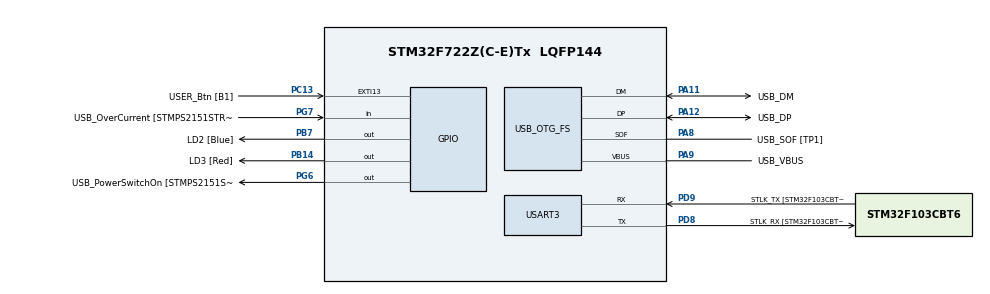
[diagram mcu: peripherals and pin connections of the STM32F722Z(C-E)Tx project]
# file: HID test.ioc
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Mcu.Family=STM32F7
Mcu.Name=STM32F722Z(C-E)Tx
Mcu.Package=LQFP144
NVIC.OTG_FS_IRQn=true\:0\:0\:false\:false\:true\:false
NVIC.PriorityGroup=NVIC_PRIORITYGROUP_4
PA10.GPIO_Label=USB_ID
PA10.Signal=USB_OTG_FS_ID
PA11.GPIO_Label=USB_DM
PA11.Mode=Device_Only
PA11.Signal=USB_OTG_FS_DM
PA12.GPIO_Label=USB_DP
PA12.Mode=Device_Only
PA12.Signal=USB_OTG_FS_DP
PA13.GPIO_Label=TMS
PA13.Mode=Serial_Wire
PA13.Signal=SYS_JTMS-SWDIO
PA14.GPIO_Label=TCK
PA14.Mode=Serial_Wire
PA14.Signal=SYS_JTCK-SWCLK
PA8.GPIO_Label=USB_SOF [TP1]
PA8.Mode=Activate_SOF_FS
PA8.Signal=USB_OTG_FS_SOF
PA9.GPIO_Label=USB_VBUS
PA9.Mode=Activate_VBUS
PA9.Signal=USB_OTG_FS_VBUS
PB14.GPIO_Label=LD3 [Red]
PB14.Signal=GPIO_Output
PB3.GPIO_Label=SWO
PB3.Signal=SYS_JTDO-SWO
PB7.GPIO_Label=LD2 [Blue]
PB7.Signal=GPIO_Output
PC13.GPIO_Label=USER_Btn [B1]
PC13.Signal=GPXTI13
PC14-OSC32_IN.Mode=LSE-External-Oscillator
PC14-OSC32_IN.Signal=RCC_OSC32_IN
PC15-OSC32_OUT.Mode=LSE-External-Oscillator
PC15-OSC32_OUT.Signal=RCC_OSC32_OUT
PD8.GPIO_Label=STLK_RX [STM32F103CBT6_PA3]
PD8.Mode=Asynchronous
PD8.Signal=USART3_TX
PD9.GPIO_Label=STLK_TX [STM32F103CBT6_PA2]
PD9.Mode=Asynchronous
PD9.Signal=USART3_RX
PG6.GPIO_Label=USB_PowerSwitchOn [STMPS2151STR_EN]
PG6.Signal=GPIO_Output
PG7.GPIO_Label=USB_OverCurrent [STMPS2151STR_FAULT]
PG7.Signal=GPIO_Input
PH0-OSC_IN.GPIO_Label=MCO
PH0-OSC_IN.Mode=HSE-External-Clock-Source
PH0-OSC_IN.Signal=RCC_OSC_IN
PH1-OSC_OUT.Mode=HSE-External-Clock-Source
PH1-OSC_OUT.Signal=RCC_OSC_OUT
ProjectManager.HeapSize=0x200
ProjectManager.StackSize=0x400
ProjectManager.TargetToolchain=Makefile
RCC.48MHZClocksFreq_Value=24000000
RCC.AHBFreq_Value=216000000
RCC.APB1CLKDivider=RCC_HCLK_DIV4
RCC.APB1Freq_Value=54000000
RCC.APB1TimFreq_Value=108000000
RCC.APB2CLKDivider=RCC_HCLK_DIV2
RCC.APB2Freq_Value=108000000
RCC.APB2TimFreq_Value=216000000
RCC.CortexFreq_Value=216000000
RCC.HCLKFreq_Value=216000000
RCC.HSE_VALUE=25000000
RCC.HSI_VALUE=16000000
RCC.PLLM=25
RCC.PLLMUL=RCC_PLL_MUL9
RCC.PLLN=432
RCC.PLLQ=9
RCC.PRESCALERUSB=RCC_USBCLKSOURCE_PLL_DIV1_5
RCC.SYSCLKFreq_VALUE=216000000
RCC.SYSCLKSource=RCC_SYSCLKSOURCE_PLLCLK
RCC.SYSCLKSourceVirtual=RCC_SYSCLKSOURCE_PLLCLK
RCC.USBFreq_Value=48000000
RCC.VCOOutputFreq_Value=432000000
USART3.VirtualMode-Asynchronous=VM_ASYNC
USB_DEVICE.CLASS_NAME_FS=HID
USB_DEVICE.VirtualMode-HID_FS=Hid
USB_DEVICE.VirtualModeFS=Hid_FS
USB_OTG_FS.VirtualMode=Device_Only
VP_USB_DEVICE_VS_USB_DEVICE_HID_FS.Mode=HID_FS
board=NUCLEO-F722ZE

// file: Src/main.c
/* USER CODE BEGIN Header */
/**
  ******************************************************************************
  * @file           : main.c
  * @brief          : Main program body
  ******************************************************************************
  * This notice applies to any and all portions of this file
  * that are not between comment pairs USER CODE BEGIN and
  * USER CODE END. Other portions of this file, whether
  * inserted by the user or by software development tools
  * are owned by their respective copyright owners.
  *
  * Copyright (c) 2019 STMicroelectronics International N.V.
  * All rights reserved.
  *
  * Redistribution and use in source and binary forms, with or without
  * modification, are permitted, provided that the following conditions are met:
  *
  * 1. Redistribution of source code must retain the above copyright notice,
  *    this list of conditions and the following disclaimer.
  * 2. Redistributions in binary form must reproduce the above copyright notice,
  *    this list of conditions and the following disclaimer in the documentation
  *    and/or other materials provided with the distribution.
  * 3. Neither the name of STMicroelectronics nor the names of other
  *    contributors to this software may be used to endorse or promote products
  *    derived from this software without specific written permission.
  * 4. This software, including modifications and/or derivative works of this
  *    software, must execute solely and exclusively on microcontroller or
  *    microprocessor devices manufactured by or for STMicroelectronics.
  * 5. Redistribution and use of this software other than as permitted under
  *    this license is void and will automatically terminate your rights under
  *    this license.
  *
  * THIS SOFTWARE IS PROVIDED BY STMICROELECTRONICS AND CONTRIBUTORS "AS IS"
  * AND ANY EXPRESS, IMPLIED OR STATUTORY WARRANTIES, INCLUDING, BUT NOT
  * LIMITED TO, THE IMPLIED WARRANTIES OF MERCHANTABILITY, FITNESS FOR A
  * PARTICULAR PURPOSE AND NON-INFRINGEMENT OF THIRD PARTY INTELLECTUAL PROPERTY
  * RIGHTS ARE DISCLAIMED TO THE FULLEST EXTENT PERMITTED BY LAW. IN NO EVENT
  * SHALL STMICROELECTRONICS OR CONTRIBUTORS BE LIABLE FOR ANY DIRECT, INDIRECT,
  * INCIDENTAL, SPECIAL, EXEMPLARY, OR CONSEQUENTIAL DAMAGES (INCLUDING, BUT NOT
  * LIMITED TO, PROCUREMENT OF SUBSTITUTE GOODS OR SERVICES; LOSS OF USE, DATA,
  * OR PROFITS; OR BUSINESS INTERRUPTION) HOWEVER CAUSED AND ON ANY THEORY OF
  * LIABILITY, WHETHER IN CONTRACT, STRICT LIABILITY, OR TORT (INCLUDING
  * NEGLIGENCE OR OTHERWISE) ARISING IN ANY WAY OUT OF THE USE OF THIS SOFTWARE,
  * EVEN IF ADVISED OF THE POSSIBILITY OF SUCH DAMAGE.
  *
  ******************************************************************************
  */
/* USER CODE END Header */

#include "main.h"
#include "usb_device.h"

UART_HandleTypeDef huart3;

void SystemClock_Config(void);
static void MX_GPIO_Init(void);
static void MX_USART3_UART_Init(void);

int main(void)
{
  /* USER CODE BEGIN 1 */
    uint8_t buffer[]="Hello world!";
  /* USER CODE END 1 */

  /* MCU Configuration--------------------------------------------------------*/

  /* Reset of all peripherals, Initializes the Flash interface and the Systick. */
  HAL_Init();

  /* Configure the system clock */
  SystemClock_Config();

  /* Initialize all configured peripherals */
  MX_GPIO_Init();
  MX_USART3_UART_Init();
  MX_USB_DEVICE_Init();

  /* Infinite loop */
  while (1)
  {

    /* USER CODE BEGIN 3 */
      //CDC_Transmit_FS(buffer,sizeof(buffer));
  }
  /* USER CODE END 3 */
}

void SystemClock_Config(void)
{
  RCC_OscInitTypeDef RCC_OscInitStruct = {0};
  RCC_ClkInitTypeDef RCC_ClkInitStruct = {0};
  RCC_PeriphCLKInitTypeDef PeriphClkInitStruct = {0};

  /**Configure LSE Drive Capability
  */
  HAL_PWR_EnableBkUpAccess();
  /**Configure the main internal regulator output voltage
  */
  __HAL_RCC_PWR_CLK_ENABLE();
  __HAL_PWR_VOLTAGESCALING_CONFIG(PWR_REGULATOR_VOLTAGE_SCALE3);
  /**Initializes the CPU, AHB and APB busses clocks
  */
  RCC_OscInitStruct.OscillatorType = RCC_OSCILLATORTYPE_HSE;
  RCC_OscInitStruct.HSEState = RCC_HSE_BYPASS;
  RCC_OscInitStruct.PLL.PLLState = RCC_PLL_ON;
  RCC_OscInitStruct.PLL.PLLSource = RCC_PLLSOURCE_HSE;
  RCC_OscInitStruct.PLL.PLLM = 15;
  RCC_OscInitStruct.PLL.PLLN = 144;
  RCC_OscInitStruct.PLL.PLLP = RCC_PLLP_DIV2;
  RCC_OscInitStruct.PLL.PLLQ = 5;
  if (HAL_RCC_OscConfig(&RCC_OscInitStruct) != HAL_OK)
  {
    Error_Handler();
  }
  /**Initializes the CPU, AHB and APB busses clocks
  */
  RCC_ClkInitStruct.ClockType = RCC_CLOCKTYPE_HCLK|RCC_CLOCKTYPE_SYSCLK
                              |RCC_CLOCKTYPE_PCLK1|RCC_CLOCKTYPE_PCLK2;
  RCC_ClkInitStruct.SYSCLKSource = RCC_SYSCLKSOURCE_PLLCLK;
  RCC_ClkInitStruct.AHBCLKDivider = RCC_SYSCLK_DIV1;
  RCC_ClkInitStruct.APB1CLKDivider = RCC_HCLK_DIV4;
  RCC_ClkInitStruct.APB2CLKDivider = RCC_HCLK_DIV2;

  if (HAL_RCC_ClockConfig(&RCC_ClkInitStruct, FLASH_LATENCY_3) != HAL_OK)
  {
    Error_Handler();
  }
  PeriphClkInitStruct.PeriphClockSelection = RCC_PERIPHCLK_USART3|RCC_PERIPHCLK_CLK48;
  PeriphClkInitStruct.Usart3ClockSelection = RCC_USART3CLKSOURCE_PCLK1;
  PeriphClkInitStruct.Clk48ClockSelection = RCC_CLK48SOURCE_PLL;
  if (HAL_RCCEx_PeriphCLKConfig(&PeriphClkInitStruct) != HAL_OK)
  {
    Error_Handler();
  }
}

static void MX_USART3_UART_Init(void)
{

  huart3.Instance = USART3;
  huart3.Init.BaudRate = 115200;
  huart3.Init.WordLength = UART_WORDLENGTH_8B;
  huart3.Init.StopBits = UART_STOPBITS_1;
  huart3.Init.Parity = UART_PARITY_NONE;
  huart3.Init.Mode = UART_MODE_TX_RX;
  huart3.Init.HwFlowCtl = UART_HWCONTROL_NONE;
  huart3.Init.OverSampling = UART_OVERSAMPLING_16;
  huart3.Init.OneBitSampling = UART_ONE_BIT_SAMPLE_DISABLE;
  huart3.AdvancedInit.AdvFeatureInit = UART_ADVFEATURE_NO_INIT;
  if (HAL_UART_Init(&huart3) != HAL_OK)
  {
    Error_Handler();
  }

}

static void MX_GPIO_Init(void)
{
  GPIO_InitTypeDef GPIO_InitStruct = {0};

  /* GPIO Ports Clock Enable */
  __HAL_RCC_GPIOC_CLK_ENABLE();
  __HAL_RCC_GPIOH_CLK_ENABLE();
  __HAL_RCC_GPIOB_CLK_ENABLE();
  __HAL_RCC_GPIOD_CLK_ENABLE();
  __HAL_RCC_GPIOG_CLK_ENABLE();
  __HAL_RCC_GPIOA_CLK_ENABLE();

  /*Configure GPIO pin Output Level */
  HAL_GPIO_WritePin(GPIOB, LD3_Pin|LD2_Pin, GPIO_PIN_RESET);

  /*Configure GPIO pin Output Level */
  HAL_GPIO_WritePin(USB_PowerSwitchOn_GPIO_Port, USB_PowerSwitchOn_Pin, GPIO_PIN_RESET);

  /*Configure GPIO pin : USER_Btn_Pin */
  GPIO_InitStruct.Pin = USER_Btn_Pin;
  GPIO_InitStruct.Mode = GPIO_MODE_IT_RISING;
  GPIO_InitStruct.Pull = GPIO_NOPULL;
  HAL_GPIO_Init(USER_Btn_GPIO_Port, &GPIO_InitStruct);

  /*Configure GPIO pins : LD3_Pin LD2_Pin */
  GPIO_InitStruct.Pin = LD3_Pin|LD2_Pin;
  GPIO_InitStruct.Mode = GPIO_MODE_OUTPUT_PP;
  GPIO_InitStruct.Pull = GPIO_NOPULL;
  GPIO_InitStruct.Speed = GPIO_SPEED_FREQ_LOW;
  HAL_GPIO_Init(GPIOB, &GPIO_InitStruct);

  /*Configure GPIO pin : USB_PowerSwitchOn_Pin */
  GPIO_InitStruct.Pin = USB_PowerSwitchOn_Pin;
  GPIO_InitStruct.Mode = GPIO_MODE_OUTPUT_PP;
  GPIO_InitStruct.Pull = GPIO_NOPULL;
  GPIO_InitStruct.Speed = GPIO_SPEED_FREQ_LOW;
  HAL_GPIO_Init(USB_PowerSwitchOn_GPIO_Port, &GPIO_InitStruct);

  /*Configure GPIO pin : USB_OverCurrent_Pin */
  GPIO_InitStruct.Pin = USB_OverCurrent_Pin;
  GPIO_InitStruct.Mode = GPIO_MODE_INPUT;
  GPIO_InitStruct.Pull = GPIO_NOPULL;
  HAL_GPIO_Init(USB_OverCurrent_GPIO_Port, &GPIO_InitStruct);

}

void Error_Handler(void)
{
}

/************************ (C) COPYRIGHT STMicroelectronics *****END OF FILE****/
